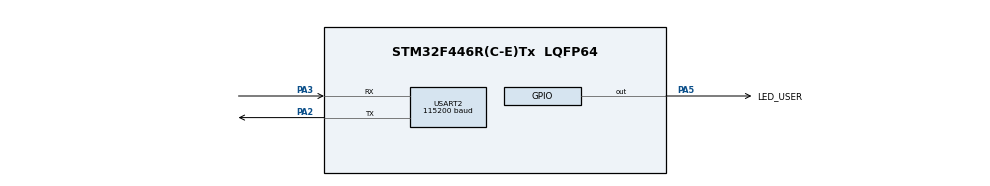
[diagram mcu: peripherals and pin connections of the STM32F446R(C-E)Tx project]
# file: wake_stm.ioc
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Mcu.Family=STM32F4
Mcu.Name=STM32F446R(C-E)Tx
Mcu.Package=LQFP64
NVIC.PriorityGroup=NVIC_PRIORITYGROUP_4
NVIC.TIM6_DAC_IRQn=true\:0\:0\:false\:false\:true\:true\:true
PA13.Mode=Serial_Wire
PA13.Signal=SYS_JTMS-SWDIO
PA14.Mode=Serial_Wire
PA14.Signal=SYS_JTCK-SWCLK
PA2.Mode=Asynchronous
PA2.Signal=USART2_TX
PA3.Mode=Asynchronous
PA3.Signal=USART2_RX
PA5.GPIO_Label=LED_USER
PA5.GPIO_Speed=GPIO_SPEED_FREQ_HIGH
PA5.PinState=GPIO_PIN_RESET
PA5.Signal=GPIO_Output
ProjectManager.HeapSize=0x200
ProjectManager.StackSize=0x400
ProjectManager.TargetToolchain=STM32CubeIDE
RCC.AHBFreq_Value=50000000
RCC.APB1CLKDivider=RCC_HCLK_DIV2
RCC.APB1Freq_Value=25000000
RCC.APB1TimFreq_Value=50000000
RCC.APB2Freq_Value=50000000
RCC.APB2TimFreq_Value=50000000
RCC.CortexFreq_Value=50000000
RCC.HCLKFreq_Value=50000000
RCC.PLLM=8
RCC.PLLN=50
RCC.SYSCLKFreq_VALUE=50000000
RCC.SYSCLKSource=RCC_SYSCLKSOURCE_PLLCLK
RCC.USBFreq_Value=50000000
RCC.VCOOutputFreq_Value=100000000
TIM6.AutoReloadPreload=TIM_AUTORELOAD_PRELOAD_DISABLE
TIM6.Period=199
TIM6.Prescaler=44999
USART2.BaudRate=115200
USART2.Mode=MODE_TX_RX
USART2.VirtualMode=VM_ASYNC
VP_TIM6_VS_ClockSourceINT.Mode=Enable_Timer
board=custom

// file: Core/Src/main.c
/* USER CODE BEGIN Header */
/**
  ******************************************************************************
  * @file           : main.c
  * @brief          : Main program body
  ******************************************************************************
  * @attention
  *
  * <h2><center>&copy; Copyright (c) 2019 STMicroelectronics.
  * All rights reserved.</center></h2>
  *
  * This software component is licensed by ST under BSD 3-Clause license,
  * the "License"; You may not use this file except in compliance with the
  * License. You may obtain a copy of the License at:
  *                        opensource.org/licenses/BSD-3-Clause
  *
  ******************************************************************************
  */
/* USER CODE END Header */

#include "main.h"
#include "tim.h"
#include "usart.h"
#include "gpio.h"

/* USER CODE BEGIN PV */
uint8_t led_toggle = 0;
/* USER CODE END PV */

void SystemClock_Config(void);

int main(void)
{

  /* MCU Configuration--------------------------------------------------------*/

  /* Reset of all peripherals, Initializes the Flash interface and the Systick. */
  HAL_Init();

  /* Configure the system clock */
  SystemClock_Config();

  /* Initialize all configured peripherals */
  MX_GPIO_Init();
  MX_USART2_UART_Init();
  MX_TIM6_Init();
  /* USER CODE BEGIN 2 */
  HAL_TIM_Base_Start_IT(&htim6);
  /* USER CODE END 2 */

  /* Infinite loop */
  while (1)
  {

  }
}

void SystemClock_Config(void)
{
  RCC_OscInitTypeDef RCC_OscInitStruct = {0};
  RCC_ClkInitTypeDef RCC_ClkInitStruct = {0};

  /** Configure the main internal regulator output voltage
  */
  __HAL_RCC_PWR_CLK_ENABLE();
  __HAL_PWR_VOLTAGESCALING_CONFIG(PWR_REGULATOR_VOLTAGE_SCALE3);
  /** Initializes the CPU, AHB and APB busses clocks
  */
  RCC_OscInitStruct.OscillatorType = RCC_OSCILLATORTYPE_HSI;
  RCC_OscInitStruct.HSIState = RCC_HSI_ON;
  RCC_OscInitStruct.HSICalibrationValue = RCC_HSICALIBRATION_DEFAULT;
  RCC_OscInitStruct.PLL.PLLState = RCC_PLL_NONE;
  if (HAL_RCC_OscConfig(&RCC_OscInitStruct) != HAL_OK)
  {
    Error_Handler();
  }
  /** Initializes the CPU, AHB and APB busses clocks
  */
  RCC_ClkInitStruct.ClockType = RCC_CLOCKTYPE_HCLK|RCC_CLOCKTYPE_SYSCLK
                              |RCC_CLOCKTYPE_PCLK1|RCC_CLOCKTYPE_PCLK2;
  RCC_ClkInitStruct.SYSCLKSource = RCC_SYSCLKSOURCE_HSI;
  RCC_ClkInitStruct.AHBCLKDivider = RCC_SYSCLK_DIV1;
  RCC_ClkInitStruct.APB1CLKDivider = RCC_HCLK_DIV1;
  RCC_ClkInitStruct.APB2CLKDivider = RCC_HCLK_DIV1;

  if (HAL_RCC_ClockConfig(&RCC_ClkInitStruct, FLASH_LATENCY_0) != HAL_OK)
  {
    Error_Handler();
  }
}

/* USER CODE BEGIN 4 */
void HAL_TIM_PeriodElapsedCallback(TIM_HandleTypeDef *htim) {
	if (htim->Instance == TIM6) {
		led_toggle = !led_toggle;
		HAL_GPIO_WritePin(LED_USER_GPIO_Port, LED_USER_Pin, led_toggle);
	}
}
/* USER CODE END 4 */

void Error_Handler(void)
{
}

/************************ (C) COPYRIGHT STMicroelectronics *****END OF FILE****/
